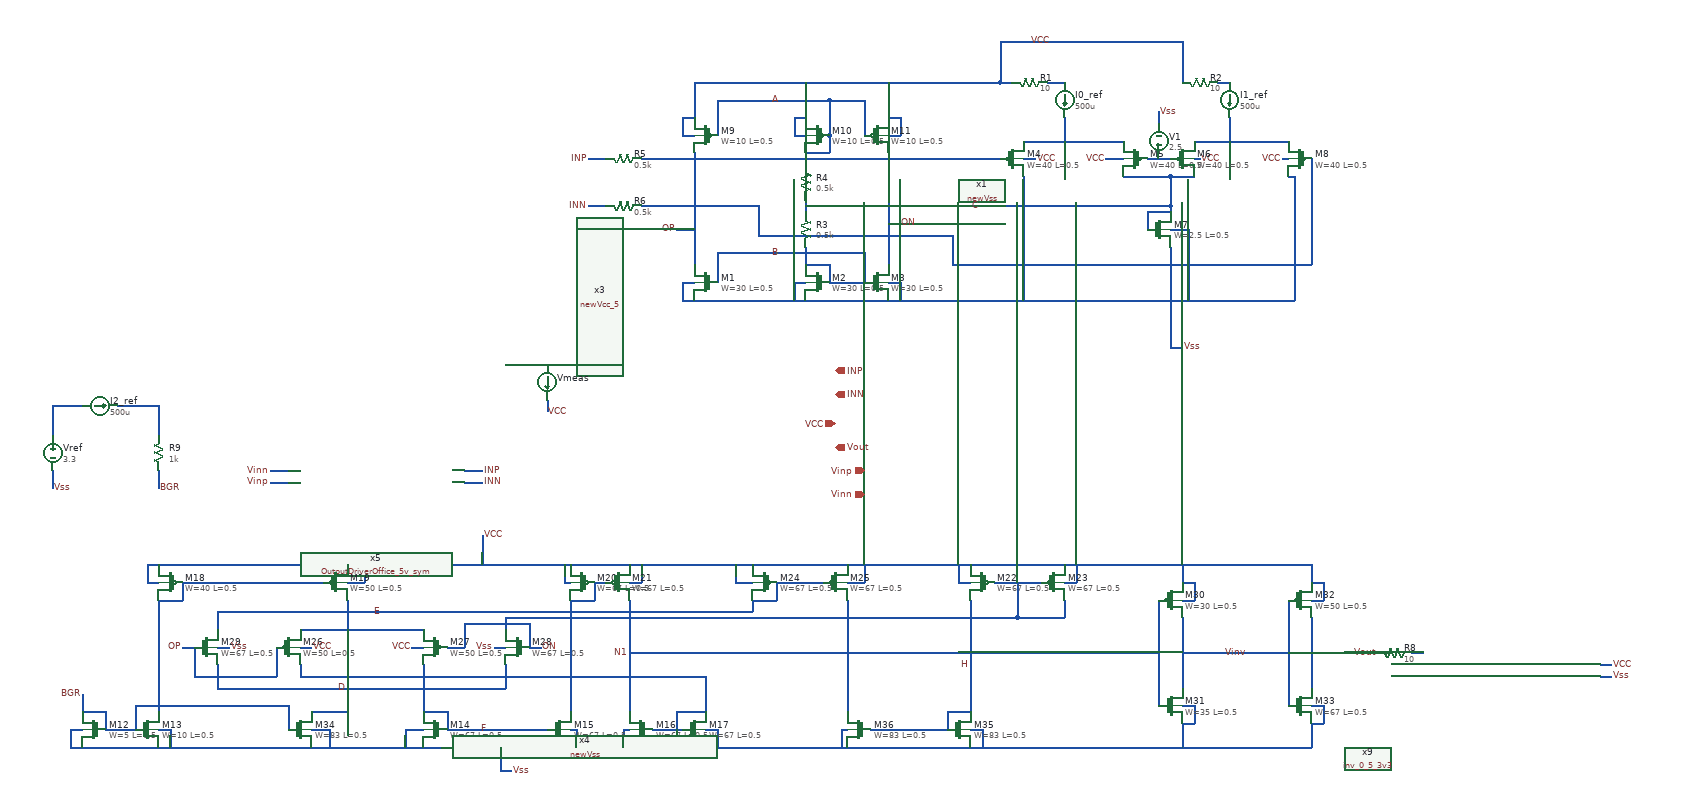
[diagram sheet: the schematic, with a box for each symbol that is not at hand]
v {xschem version=3.4.2 file_version=1.2
}
G {}
K {}
V {}
S {}
E {}
N -170 120 -140 120 {
lab=INP}
N -170 140 -140 140 {
lab=INN}
N -500 120 -470 120 {
lab=Vinn}
N -500 140 -470 140 {
lab=Vinp}
N 550 -420 550 -230 {
lab=ON}
N 780 -440 950 -440 {
lab=#net1}
N 1070 -440 1230 -440 {
lab=#net2}
N 220 -540 220 -480 {
lab=VCC}
N 1130 -480 1130 -440 {
lab=#net2}
N 850 -480 850 -440 {
lab=#net1}
N 990 -410 1030 -410 {
lab=#net3}
N 220 -170 1240 -170 {
lab=Vss}
N 1240 -380 1240 -170 {
lab=Vss}
N 1230 -380 1240 -380 {
lab=Vss}
N 410 -540 410 -480 {
lab=VCC}
N 550 -540 550 -480 {
lab=VCC}
N 220 -340 220 -320 {
lab=OP}
N 220 -420 220 -400 {
lab=OP}
N 220 -260 220 -230 {
lab=OP}
N 410 -420 410 -400 {
lab=A}
N 410 -340 410 -320 {
lab=C}
N 410 -260 410 -230 {
lab=B}
N 410 -330 1030 -330 {
lab=C}
N 1030 -380 1030 -330 {
lab=C}
N 1030 -380 1070 -380 {
lab=C}
N 950 -380 1030 -380 {
lab=C}
N 780 -380 780 -170 {
lab=Vss}
N 1030 -330 1030 -320 {
lab=C}
N 1270 -410 1270 -230 {
lab=ON}
N 660 -230 1270 -230 {
lab=ON}
N 660 -240 660 -230 {
lab=ON}
N 260 -510 260 -450 {
lab=A}
N 260 -510 450 -510 {
lab=A}
N 450 -510 450 -450 {
lab=A}
N 450 -510 510 -510 {
lab=A}
N 510 -510 510 -450 {
lab=A}
N 450 -510 450 -450 {
lab=A}
N 40 -410 70 -410 {
lab=INP}
N 40 -330 70 -330 {
lab=INN}
N 260 -250 260 -200 {
lab=B}
N 260 -250 450 -250 {
lab=B}
N 450 -250 510 -250 {
lab=B}
N 510 -250 510 -200 {
lab=B}
N 200 -200 220 -200 {
lab=Vss}
N 200 -200 200 -170 {
lab=Vss}
N 200 -170 220 -170 {
lab=Vss}
N 390 -200 410 -200 {
lab=Vss}
N 390 -200 390 -170 {
lab=Vss}
N 550 -200 570 -200 {
lab=Vss}
N 570 -200 570 -170 {
lab=Vss}
N 1030 -290 1060 -290 {
lab=Vss}
N 1060 -290 1060 -170 {
lab=Vss}
N 1220 -410 1230 -410 {
lab=VCC}
N 740 -610 740 -540 {
lab=VCC}
N 740 -610 790 -610 {
lab=VCC}
N 920 -410 950 -410 {
lab=VCC}
N 780 -410 800 -410 {
lab=VCC}
N 550 -450 570 -450 {
lab=VCC}
N 570 -480 570 -450 {
lab=VCC}
N 550 -480 570 -480 {
lab=VCC}
N 390 -450 410 -450 {
lab=VCC}
N 390 -480 390 -450 {
lab=VCC}
N 390 -480 410 -480 {
lab=VCC}
N 200 -450 220 -450 {
lab=VCC}
N 200 -480 200 -450 {
lab=VCC}
N 200 -480 220 -480 {
lab=VCC}
N 1070 -410 1080 -410 {
lab=VCC}
N 1030 -260 1030 -170 {
lab=Vss}
N 1030 -170 1030 -90 {
lab=Vss}
N 220 -400 220 -340 {
lab=OP}
N 220 -320 220 -260 {
lab=OP}
N 190 -290 220 -290 {
lab=OP}
N 550 -300 570 -300 {
lab=ON}
N 410 -420 450 -420 {
lab=A}
N 450 -450 450 -420 {
lab=A}
N 820 -540 850 -540 {
lab=#net4}
N 790 -610 1050 -610 {
lab=VCC}
N 1050 -610 1050 -540 {
lab=VCC}
N 1110 -540 1130 -540 {
lab=#net5}
N 740 -540 760 -540 {
lab=VCC}
N 220 -540 740 -540 {
lab=VCC}
N 130 -410 220 -410 {
lab=OP}
N 220 -410 740 -410 {
lab=OP}
N 550 -280 660 -280 {
lab=ON}
N 660 -280 660 -240 {
lab=ON}
N 130 -330 320 -330 {
lab=ON}
N 320 -330 330 -330 {
lab=ON}
N 450 -230 450 -200 {
lab=B}
N 410 -230 450 -230 {
lab=B}
N 990 -320 990 -290 {
lab=C}
N 990 -320 1030 -320 {
lab=C}
N 330 -330 330 -280 {
lab=ON}
N 330 -280 550 -280 {
lab=ON}
N 450 -200 510 -200 {
lab=B}
N 1010 -490 1010 -470 {
lab=Vss}
N 1030 -90 1050 -90 {
lab=Vss}
N -650 310 -410 310 {
lab=#net6}
N 730 310 810 310 {
lab=#net7}
N 360 310 440 310 {
lab=E}
N -690 280 1270 280 {
lab=VCC}
N 1270 280 1270 310 {
lab=VCC}
N 1050 280 1050 310 {
lab=VCC}
N 1050 370 1050 490 {
lab=Vinv}
N 1270 370 1270 490 {
lab=Vout}
N -690 340 -690 530 {
lab=#net6}
N -450 390 -240 390 {
lab=#net8}
N -370 340 -370 390 {
lab=#net8}
N -590 450 -590 490 {
lab=D}
N -590 490 -230 490 {
lab=D}
N -370 490 -370 530 {
lab=D}
N -430 530 -370 530 {
lab=D}
N -240 450 -240 530 {
lab=F}
N -780 560 -730 560 {
lab=BGR}
N -730 520 -730 560 {
lab=BGR}
N -730 520 -470 520 {
lab=BGR}
N -470 520 -470 560 {
lab=BGR}
N -240 530 -200 530 {
lab=F}
N -200 530 -200 560 {
lab=F}
N -200 560 -110 560 {
lab=F}
N 10 340 10 530 {
lab=#net9}
N 170 560 200 560 {
lab=#net10}
N 190 530 190 560 {
lab=#net10}
N 190 530 240 530 {
lab=#net10}
N -450 450 -450 470 {
lab=#net10}
N 110 340 110 530 {
lab=N1}
N -450 470 240 470 {
lab=#net10}
N 240 470 240 530 {
lab=#net10}
N 1270 550 1270 570 {
lab=Vss}
N 1270 570 1270 590 {
lab=Vss}
N -820 590 1270 590 {
lab=Vss}
N 1050 550 1050 590 {
lab=Vss}
N 1230 340 1230 520 {
lab=Vinv}
N 1050 430 1230 430 {
lab=Vinv}
N 1270 430 1340 430 {
lab=Vout}
N -820 500 -820 530 {
lab=BGR}
N -650 420 -630 420 {
lab=OP}
N 690 340 690 500 {
lab=H}
N 490 590 710 590 {
lab=Vss}
N 1010 340 1010 520 {
lab=N1}
N 690 500 690 520 {
lab=H}
N 690 520 690 530 {
lab=H}
N 150 560 170 560 {
lab=#net10}
N 110 430 320 430 {
lab=N1}
N 770 310 770 350 {
lab=#net7}
N -240 590 -210 590 {
lab=Vss}
N -370 280 -340 280 {
lab=VCC}
N -430 590 -400 590 {
lab=Vss}
N -200 420 -170 420 {
lab=ON}
N -60 420 -40 420 {
lab=ON}
N 480 340 480 530 {
lab=N1}
N 520 560 650 560 {
lab=H}
N -110 560 -30 560 {
lab=F}
N -230 490 -100 490 {
lab=D}
N -100 450 -100 490 {
lab=D}
N -60 380 -60 420 {
lab=ON}
N -170 380 -60 380 {
lab=ON}
N -170 380 -170 420 {
lab=ON}
N -590 370 -590 390 {
lab=E}
N -490 420 -490 470 {
lab=OP}
N -620 470 -490 470 {
lab=OP}
N -630 470 -620 470 {
lab=OP}
N -630 420 -630 470 {
lab=OP}
N 50 310 70 310 {
lab=#net9}
N -590 360 -590 370 {
lab=E}
N 1270 340 1290 340 {
lab=VCC}
N 1290 310 1290 340 {
lab=VCC}
N 1270 310 1290 310 {
lab=VCC}
N 1270 520 1290 520 {
lab=Vss}
N 1290 520 1290 550 {
lab=Vss}
N 1270 550 1290 550 {
lab=Vss}
N 1050 520 1070 520 {
lab=Vss}
N 1070 520 1070 550 {
lab=Vss}
N 1050 550 1070 550 {
lab=Vss}
N 1050 340 1070 340 {
lab=VCC}
N 1070 310 1070 340 {
lab=VCC}
N 1050 310 1070 310 {
lab=VCC}
N 850 310 870 310 {
lab=VCC}
N 870 280 870 310 {
lab=VCC}
N 670 310 690 310 {
lab=VCC}
N 670 280 670 310 {
lab=VCC}
N 480 310 510 310 {
lab=VCC}
N 510 280 510 310 {
lab=VCC}
N 290 310 320 310 {
lab=VCC}
N 290 280 290 310 {
lab=VCC}
N 110 310 130 310 {
lab=VCC}
N 130 280 130 310 {
lab=VCC}
N 0 310 10 310 {
lab=VCC}
N 0 280 0 310 {
lab=VCC}
N -370 310 -340 310 {
lab=VCC}
N -340 280 -340 310 {
lab=VCC}
N -710 310 -690 310 {
lab=VCC}
N -710 280 -710 310 {
lab=VCC}
N -710 280 -690 280 {
lab=VCC}
N -840 560 -820 560 {
lab=Vss}
N -840 560 -840 590 {
lab=Vss}
N -840 590 -820 590 {
lab=Vss}
N -690 560 -670 560 {
lab=Vss}
N -670 560 -670 590 {
lab=Vss}
N -430 560 -400 560 {
lab=Vss}
N -400 560 -400 590 {
lab=Vss}
N -270 560 -240 560 {
lab=Vss}
N -270 560 -270 590 {
lab=Vss}
N 10 560 20 560 {
lab=Vss}
N 20 560 20 590 {
lab=Vss}
N 240 560 260 560 {
lab=Vss}
N 260 560 260 590 {
lab=Vss}
N 470 560 480 560 {
lab=Vss}
N 470 560 470 590 {
lab=Vss}
N 690 560 710 560 {
lab=Vss}
N 710 560 710 590 {
lab=Vss}
N -590 420 -570 420 {
lab=Vss}
N -450 420 -430 420 {
lab=VCC}
N -260 420 -240 420 {
lab=VCC}
N -120 420 -100 420 {
lab=Vss}
N -110 590 -110 630 {
lab=Vss}
N -140 230 -140 280 {
lab=VCC}
N 100 560 110 560 {
lab=Vss}
N 100 560 100 590 {
lab=Vss}
N -110 630 -90 630 {
lab=Vss}
N 50 310 50 340 {
lab=#net9}
N 10 340 50 340 {
lab=#net9}
N 650 530 650 560 {
lab=H}
N 650 530 690 530 {
lab=H}
N -780 530 -780 560 {
lab=BGR}
N -820 530 -780 530 {
lab=BGR}
N -650 310 -650 340 {
lab=#net6}
N -690 340 -650 340 {
lab=#net6}
N -100 370 -100 390 {
lab=#net7}
N -100 370 770 370 {
lab=#net7}
N 770 350 770 370 {
lab=#net7}
N 360 310 360 340 {
lab=E}
N 320 340 360 340 {
lab=E}
N -590 360 320 360 {
lab=E}
N 320 340 320 360 {
lab=E}
N 850 340 850 370 {
lab=#net7}
N 770 370 850 370 {
lab=#net7}
N -690 120 -690 150 {
lab=BGR}
N -870 120 -870 150 {
lab=Vss}
N -870 10 -870 60 {
lab=#net11}
N -870 10 -820 10 {
lab=#net11}
N -760 10 -690 10 {
lab=#net12}
N -690 10 -690 60 {
lab=#net12}
N 320 430 480 430 {
lab=N1}
N 480 430 1010 430 {
lab=N1}
N 1340 430 1380 430 {
lab=Vout}
N 1440 430 1460 430 {
lab=#net13}
N 1760 450 1780 450 {
lab=VCC}
N 1760 470 1780 470 {
lab=Vss}
N -100 -60 -30 -60 {
lab=#net14}
N -30 0 -30 20 {
lab=VCC}
C {OutputDriverOffice_5v_sym.sym} -320 130 0 0 {name=x5}
C {devices/lab_pin.sym} -140 120 0 1 {name=p21 sig_type=std_logic lab=INP}
C {devices/lab_pin.sym} -140 140 0 1 {name=p22 sig_type=std_logic lab=INN}
C {devices/lab_pin.sym} -500 120 2 1 {name=p23 sig_type=std_logic lab=Vinn}
C {devices/lab_pin.sym} -500 140 2 1 {name=p24 sig_type=std_logic lab=Vinp}
C {sky130_fd_pr/nfet_g5v0d10v5.sym} 240 -200 0 1 {name=M1
L=0.5
W=30
nf=2
mult=1
ad="'int((nf+1)/2) * W/nf * 0.29'" 
pd="'2*int((nf+1)/2) * (W/nf + 0.29)'"
as="'int((nf+2)/2) * W/nf * 0.29'" 
ps="'2*int((nf+2)/2) * (W/nf + 0.29)'"
nrd="'0.29 / W'" nrs="'0.29 / W'"
sa=0 sb=0 sd=0
model=nfet_g5v0d10v5
spiceprefix=X
}
C {sky130_fd_pr/nfet_g5v0d10v5.sym} 430 -200 0 1 {name=M2
L=0.5
W=30
nf=2
mult=1
ad="'int((nf+1)/2) * W/nf * 0.29'" 
pd="'2*int((nf+1)/2) * (W/nf + 0.29)'"
as="'int((nf+2)/2) * W/nf * 0.29'" 
ps="'2*int((nf+2)/2) * (W/nf + 0.29)'"
nrd="'0.29 / W'" nrs="'0.29 / W'"
sa=0 sb=0 sd=0
model=nfet_g5v0d10v5
spiceprefix=X
}
C {sky130_fd_pr/nfet_g5v0d10v5.sym} 530 -200 0 0 {name=M3
L=0.5
W=30
nf=2
mult=1
ad="'int((nf+1)/2) * W/nf * 0.29'" 
pd="'2*int((nf+1)/2) * (W/nf + 0.29)'"
as="'int((nf+2)/2) * W/nf * 0.29'" 
ps="'2*int((nf+2)/2) * (W/nf + 0.29)'"
nrd="'0.29 / W'" nrs="'0.29 / W'"
sa=0 sb=0 sd=0
model=nfet_g5v0d10v5
spiceprefix=X
}
C {sky130_fd_pr/pfet_g5v0d10v5.sym} 240 -450 0 1 {name=M9
L=0.5
W=10
nf=1
mult=1
ad="'int((nf+1)/2) * W/nf * 0.29'" 
pd="'2*int((nf+1)/2) * (W/nf + 0.29)'"
as="'int((nf+2)/2) * W/nf * 0.29'" 
ps="'2*int((nf+2)/2) * (W/nf + 0.29)'"
nrd="'0.29 / W'" nrs="'0.29 / W'"
sa=0 sb=0 sd=0
model=pfet_g5v0d10v5
spiceprefix=X
}
C {sky130_fd_pr/pfet_g5v0d10v5.sym} 430 -450 0 1 {name=M10
L=0.5
W=10
nf=1
mult=1
ad="'int((nf+1)/2) * W/nf * 0.29'" 
pd="'2*int((nf+1)/2) * (W/nf + 0.29)'"
as="'int((nf+2)/2) * W/nf * 0.29'" 
ps="'2*int((nf+2)/2) * (W/nf + 0.29)'"
nrd="'0.29 / W'" nrs="'0.29 / W'"
sa=0 sb=0 sd=0
model=pfet_g5v0d10v5
spiceprefix=X
}
C {sky130_fd_pr/pfet_g5v0d10v5.sym} 530 -450 0 0 {name=M11
L=0.5
W=10
nf=1
mult=1
ad="'int((nf+1)/2) * W/nf * 0.29'" 
pd="'2*int((nf+1)/2) * (W/nf + 0.29)'"
as="'int((nf+2)/2) * W/nf * 0.29'" 
ps="'2*int((nf+2)/2) * (W/nf + 0.29)'"
nrd="'0.29 / W'" nrs="'0.29 / W'"
sa=0 sb=0 sd=0
model=pfet_g5v0d10v5
spiceprefix=X
}
C {/home/saumeek/simulation_library/newVss.sym} 880 -90 0 0 {name=x1}
C {devices/isource.sym} 850 -510 0 0 {name=I0_ref value=500u}
C {devices/isource.sym} 1130 -510 0 0 {name=I1_ref value=500u}
C {devices/res.sym} 410 -290 0 0 {name=R3
value=0.5k
footprint=1206
device=resistor
m=1}
C {devices/res.sym} 410 -370 0 0 {name=R4
value=0.5k
footprint=1206
device=resistor
m=1}
C {devices/res.sym} 100 -410 1 0 {name=R5
value=0.5k
footprint=1206
device=resistor
m=1}
C {devices/res.sym} 100 -330 1 0 {name=R6
value=0.5k
footprint=1206
device=resistor
m=1}
C {devices/lab_pin.sym} 790 -610 0 1 {name=p1 sig_type=std_logic lab=VCC}
C {devices/lab_pin.sym} 800 -410 0 1 {name=p2 sig_type=std_logic lab=VCC}
C {devices/lab_pin.sym} 920 -410 0 0 {name=p3 sig_type=std_logic lab=VCC}
C {devices/lab_pin.sym} 1080 -410 0 1 {name=p4 sig_type=std_logic lab=VCC}
C {devices/lab_pin.sym} 1220 -410 0 0 {name=p5 sig_type=std_logic lab=VCC}
C {devices/lab_pin.sym} 40 -410 0 0 {name=p6 sig_type=std_logic lab=INP}
C {devices/lab_pin.sym} 40 -330 0 0 {name=p7 sig_type=std_logic lab=INN}
C {devices/lab_pin.sym} 190 -290 0 0 {name=p8 sig_type=std_logic lab=OP}
C {devices/lab_pin.sym} 570 -300 0 1 {name=p9 sig_type=std_logic lab=ON}
C {sky130_fd_pr/nfet_g5v0d10v5.sym} 1010 -290 0 0 {name=M7
L=0.5
W=2.5
nf=1
mult=1
ad="'int((nf+1)/2) * W/nf * 0.29'" 
pd="'2*int((nf+1)/2) * (W/nf + 0.29)'"
as="'int((nf+2)/2) * W/nf * 0.29'" 
ps="'2*int((nf+2)/2) * (W/nf + 0.29)'"
nrd="'0.29 / W'" nrs="'0.29 / W'"
sa=0 sb=0 sd=0
model=nfet_g5v0d10v5
spiceprefix=X
}
C {sky130_fd_pr/pfet_g5v0d10v5.sym} 760 -410 0 0 {name=M4
L=0.5
W=40
nf=1
mult=1
ad="'int((nf+1)/2) * W/nf * 0.29'" 
pd="'2*int((nf+1)/2) * (W/nf + 0.29)'"
as="'int((nf+2)/2) * W/nf * 0.29'" 
ps="'2*int((nf+2)/2) * (W/nf + 0.29)'"
nrd="'0.29 / W'" nrs="'0.29 / W'"
sa=0 sb=0 sd=0
model=pfet_g5v0d10v5
spiceprefix=X
}
C {sky130_fd_pr/pfet_g5v0d10v5.sym} 970 -410 0 1 {name=M5
L=0.5
W=40
nf=1
mult=1
ad="'int((nf+1)/2) * W/nf * 0.29'" 
pd="'2*int((nf+1)/2) * (W/nf + 0.29)'"
as="'int((nf+2)/2) * W/nf * 0.29'" 
ps="'2*int((nf+2)/2) * (W/nf + 0.29)'"
nrd="'0.29 / W'" nrs="'0.29 / W'"
sa=0 sb=0 sd=0
model=pfet_g5v0d10v5
spiceprefix=X
}
C {sky130_fd_pr/pfet_g5v0d10v5.sym} 1050 -410 0 0 {name=M6
L=0.5
W=40
nf=1
mult=1
ad="'int((nf+1)/2) * W/nf * 0.29'" 
pd="'2*int((nf+1)/2) * (W/nf + 0.29)'"
as="'int((nf+2)/2) * W/nf * 0.29'" 
ps="'2*int((nf+2)/2) * (W/nf + 0.29)'"
nrd="'0.29 / W'" nrs="'0.29 / W'"
sa=0 sb=0 sd=0
model=pfet_g5v0d10v5
spiceprefix=X
}
C {sky130_fd_pr/pfet_g5v0d10v5.sym} 1250 -410 0 1 {name=M8
L=0.5
W=40
nf=1
mult=1
ad="'int((nf+1)/2) * W/nf * 0.29'" 
pd="'2*int((nf+1)/2) * (W/nf + 0.29)'"
as="'int((nf+2)/2) * W/nf * 0.29'" 
ps="'2*int((nf+2)/2) * (W/nf + 0.29)'"
nrd="'0.29 / W'" nrs="'0.29 / W'"
sa=0 sb=0 sd=0
model=pfet_g5v0d10v5
spiceprefix=X
}
C {devices/vsource.sym} 1010 -440 2 0 {name=V1 value=2.5}
C {devices/res.sym} 790 -540 1 0 {name=R1
value=10
footprint=1206
device=resistor
m=1}
C {devices/res.sym} 1080 -540 1 0 {name=R2
value=10
footprint=1206
device=resistor
m=1}
C {devices/lab_pin.sym} 350 -510 0 1 {name=p29 sig_type=std_logic lab=A}
C {devices/lab_pin.sym} 350 -250 0 1 {name=p30 sig_type=std_logic lab=B}
C {devices/lab_pin.sym} 690 -330 0 1 {name=p31 sig_type=std_logic lab=C}
C {devices/lab_pin.sym} 1010 -490 0 1 {name=p32 sig_type=std_logic lab=Vss}
C {devices/lab_pin.sym} 1050 -90 0 1 {name=p33 sig_type=std_logic lab=Vss}
C {sky130_fd_pr/nfet_g5v0d10v5.sym} -800 560 0 1 {name=M12
L=0.5
W=5
nf=1
mult=1
ad="'int((nf+1)/2) * W/nf * 0.29'" 
pd="'2*int((nf+1)/2) * (W/nf + 0.29)'"
as="'int((nf+2)/2) * W/nf * 0.29'" 
ps="'2*int((nf+2)/2) * (W/nf + 0.29)'"
nrd="'0.29 / W'" nrs="'0.29 / W'"
sa=0 sb=0 sd=0
model=nfet_g5v0d10v5
spiceprefix=X
}
C {sky130_fd_pr/nfet_g5v0d10v5.sym} -710 560 0 0 {name=M13
L=0.5
W=10
nf=1
mult=1
ad="'int((nf+1)/2) * W/nf * 0.29'" 
pd="'2*int((nf+1)/2) * (W/nf + 0.29)'"
as="'int((nf+2)/2) * W/nf * 0.29'" 
ps="'2*int((nf+2)/2) * (W/nf + 0.29)'"
nrd="'0.29 / W'" nrs="'0.29 / W'"
sa=0 sb=0 sd=0
model=nfet_g5v0d10v5
spiceprefix=X
}
C {sky130_fd_pr/nfet_g5v0d10v5.sym} -220 560 0 1 {name=M14
L=0.5
W=67
nf=1
mult=1
ad="'int((nf+1)/2) * W/nf * 0.29'" 
pd="'2*int((nf+1)/2) * (W/nf + 0.29)'"
as="'int((nf+2)/2) * W/nf * 0.29'" 
ps="'2*int((nf+2)/2) * (W/nf + 0.29)'"
nrd="'0.29 / W'" nrs="'0.29 / W'"
sa=0 sb=0 sd=0
model=nfet_g5v0d10v5
spiceprefix=X
}
C {sky130_fd_pr/nfet_g5v0d10v5.sym} -10 560 0 0 {name=M15
L=0.5
W=67
nf=1
mult=1
ad="'int((nf+1)/2) * W/nf * 0.29'" 
pd="'2*int((nf+1)/2) * (W/nf + 0.29)'"
as="'int((nf+2)/2) * W/nf * 0.29'" 
ps="'2*int((nf+2)/2) * (W/nf + 0.29)'"
nrd="'0.29 / W'" nrs="'0.29 / W'"
sa=0 sb=0 sd=0
model=nfet_g5v0d10v5
spiceprefix=X
}
C {sky130_fd_pr/nfet_g5v0d10v5.sym} 130 560 0 1 {name=M16
L=0.5
W=67
nf=1
mult=1
ad="'int((nf+1)/2) * W/nf * 0.29'" 
pd="'2*int((nf+1)/2) * (W/nf + 0.29)'"
as="'int((nf+2)/2) * W/nf * 0.29'" 
ps="'2*int((nf+2)/2) * (W/nf + 0.29)'"
nrd="'0.29 / W'" nrs="'0.29 / W'"
sa=0 sb=0 sd=0
model=nfet_g5v0d10v5
spiceprefix=X
}
C {sky130_fd_pr/nfet_g5v0d10v5.sym} 220 560 0 0 {name=M17
L=0.5
W=67
nf=1
mult=1
ad="'int((nf+1)/2) * W/nf * 0.29'" 
pd="'2*int((nf+1)/2) * (W/nf + 0.29)'"
as="'int((nf+2)/2) * W/nf * 0.29'" 
ps="'2*int((nf+2)/2) * (W/nf + 0.29)'"
nrd="'0.29 / W'" nrs="'0.29 / W'"
sa=0 sb=0 sd=0
model=nfet_g5v0d10v5
spiceprefix=X
}
C {sky130_fd_pr/pfet_g5v0d10v5.sym} -670 310 0 1 {name=M18
L=0.5
W=40
nf=1
mult=1
ad="'int((nf+1)/2) * W/nf * 0.29'" 
pd="'2*int((nf+1)/2) * (W/nf + 0.29)'"
as="'int((nf+2)/2) * W/nf * 0.29'" 
ps="'2*int((nf+2)/2) * (W/nf + 0.29)'"
nrd="'0.29 / W'" nrs="'0.29 / W'"
sa=0 sb=0 sd=0
model=pfet_g5v0d10v5
spiceprefix=X
}
C {sky130_fd_pr/pfet_g5v0d10v5.sym} -390 310 0 0 {name=M19
L=0.5
W=50
nf=2
mult=1
ad="'int((nf+1)/2) * W/nf * 0.29'" 
pd="'2*int((nf+1)/2) * (W/nf + 0.29)'"
as="'int((nf+2)/2) * W/nf * 0.29'" 
ps="'2*int((nf+2)/2) * (W/nf + 0.29)'"
nrd="'0.29 / W'" nrs="'0.29 / W'"
sa=0 sb=0 sd=0
model=pfet_g5v0d10v5
spiceprefix=X
}
C {sky130_fd_pr/pfet_g5v0d10v5.sym} 30 310 0 1 {name=M20
L=0.5
W=67
nf=1
mult=1
ad="'int((nf+1)/2) * W/nf * 0.29'" 
pd="'2*int((nf+1)/2) * (W/nf + 0.29)'"
as="'int((nf+2)/2) * W/nf * 0.29'" 
ps="'2*int((nf+2)/2) * (W/nf + 0.29)'"
nrd="'0.29 / W'" nrs="'0.29 / W'"
sa=0 sb=0 sd=0
model=pfet_g5v0d10v5
spiceprefix=X
}
C {sky130_fd_pr/pfet_g5v0d10v5.sym} 90 310 0 0 {name=M21
L=0.5
W=67
nf=1
mult=1
ad="'int((nf+1)/2) * W/nf * 0.29'" 
pd="'2*int((nf+1)/2) * (W/nf + 0.29)'"
as="'int((nf+2)/2) * W/nf * 0.29'" 
ps="'2*int((nf+2)/2) * (W/nf + 0.29)'"
nrd="'0.29 / W'" nrs="'0.29 / W'"
sa=0 sb=0 sd=0
model=pfet_g5v0d10v5
spiceprefix=X
}
C {sky130_fd_pr/pfet_g5v0d10v5.sym} 710 310 0 1 {name=M22
L=0.5
W=67
nf=2
mult=1
ad="'int((nf+1)/2) * W/nf * 0.29'" 
pd="'2*int((nf+1)/2) * (W/nf + 0.29)'"
as="'int((nf+2)/2) * W/nf * 0.29'" 
ps="'2*int((nf+2)/2) * (W/nf + 0.29)'"
nrd="'0.29 / W'" nrs="'0.29 / W'"
sa=0 sb=0 sd=0
model=pfet_g5v0d10v5
spiceprefix=X
}
C {sky130_fd_pr/pfet_g5v0d10v5.sym} 830 310 0 0 {name=M23
L=0.5
W=67
nf=2
mult=1
ad="'int((nf+1)/2) * W/nf * 0.29'" 
pd="'2*int((nf+1)/2) * (W/nf + 0.29)'"
as="'int((nf+2)/2) * W/nf * 0.29'" 
ps="'2*int((nf+2)/2) * (W/nf + 0.29)'"
nrd="'0.29 / W'" nrs="'0.29 / W'"
sa=0 sb=0 sd=0
model=pfet_g5v0d10v5
spiceprefix=X
}
C {sky130_fd_pr/pfet_g5v0d10v5.sym} 340 310 0 1 {name=M24
L=0.5
W=67
nf=1
mult=1
ad="'int((nf+1)/2) * W/nf * 0.29'" 
pd="'2*int((nf+1)/2) * (W/nf + 0.29)'"
as="'int((nf+2)/2) * W/nf * 0.29'" 
ps="'2*int((nf+2)/2) * (W/nf + 0.29)'"
nrd="'0.29 / W'" nrs="'0.29 / W'"
sa=0 sb=0 sd=0
model=pfet_g5v0d10v5
spiceprefix=X
}
C {sky130_fd_pr/pfet_g5v0d10v5.sym} 460 310 0 0 {name=M25
L=0.5
W=67
nf=2
mult=1
ad="'int((nf+1)/2) * W/nf * 0.29'" 
pd="'2*int((nf+1)/2) * (W/nf + 0.29)'"
as="'int((nf+2)/2) * W/nf * 0.29'" 
ps="'2*int((nf+2)/2) * (W/nf + 0.29)'"
nrd="'0.29 / W'" nrs="'0.29 / W'"
sa=0 sb=0 sd=0
model=pfet_g5v0d10v5
spiceprefix=X
}
C {sky130_fd_pr/pfet_g5v0d10v5.sym} -470 420 0 0 {name=M26
L=0.5
W=50
nf=4
mult=1
ad="'int((nf+1)/2) * W/nf * 0.29'" 
pd="'2*int((nf+1)/2) * (W/nf + 0.29)'"
as="'int((nf+2)/2) * W/nf * 0.29'" 
ps="'2*int((nf+2)/2) * (W/nf + 0.29)'"
nrd="'0.29 / W'" nrs="'0.29 / W'"
sa=0 sb=0 sd=0
model=pfet_g5v0d10v5
spiceprefix=X
}
C {sky130_fd_pr/pfet_g5v0d10v5.sym} -220 420 0 1 {name=M27
L=0.5
W=50
nf=4
mult=1
ad="'int((nf+1)/2) * W/nf * 0.29'" 
pd="'2*int((nf+1)/2) * (W/nf + 0.29)'"
as="'int((nf+2)/2) * W/nf * 0.29'" 
ps="'2*int((nf+2)/2) * (W/nf + 0.29)'"
nrd="'0.29 / W'" nrs="'0.29 / W'"
sa=0 sb=0 sd=0
model=pfet_g5v0d10v5
spiceprefix=X
}
C {sky130_fd_pr/nfet_g5v0d10v5.sym} -80 420 0 1 {name=M28
L=0.5
W=67
nf=1
mult=1
ad="'int((nf+1)/2) * W/nf * 0.29'" 
pd="'2*int((nf+1)/2) * (W/nf + 0.29)'"
as="'int((nf+2)/2) * W/nf * 0.29'" 
ps="'2*int((nf+2)/2) * (W/nf + 0.29)'"
nrd="'0.29 / W'" nrs="'0.29 / W'"
sa=0 sb=0 sd=0
model=nfet_g5v0d10v5
spiceprefix=X
}
C {sky130_fd_pr/nfet_g5v0d10v5.sym} -610 420 0 0 {name=M29
L=0.5
W=67
nf=1
mult=1
ad="'int((nf+1)/2) * W/nf * 0.29'" 
pd="'2*int((nf+1)/2) * (W/nf + 0.29)'"
as="'int((nf+2)/2) * W/nf * 0.29'" 
ps="'2*int((nf+2)/2) * (W/nf + 0.29)'"
nrd="'0.29 / W'" nrs="'0.29 / W'"
sa=0 sb=0 sd=0
model=nfet_g5v0d10v5
spiceprefix=X
}
C {sky130_fd_pr/pfet_g5v0d10v5.sym} 1030 340 0 0 {name=M30
L=0.5
W=30
nf=1
mult=1
ad="'int((nf+1)/2) * W/nf * 0.29'" 
pd="'2*int((nf+1)/2) * (W/nf + 0.29)'"
as="'int((nf+2)/2) * W/nf * 0.29'" 
ps="'2*int((nf+2)/2) * (W/nf + 0.29)'"
nrd="'0.29 / W'" nrs="'0.29 / W'"
sa=0 sb=0 sd=0
model=pfet_g5v0d10v5
spiceprefix=X
}
C {sky130_fd_pr/nfet_g5v0d10v5.sym} 1030 520 0 0 {name=M31
L=0.5
W=35
nf=2
mult=1
ad="'int((nf+1)/2) * W/nf * 0.29'" 
pd="'2*int((nf+1)/2) * (W/nf + 0.29)'"
as="'int((nf+2)/2) * W/nf * 0.29'" 
ps="'2*int((nf+2)/2) * (W/nf + 0.29)'"
nrd="'0.29 / W'" nrs="'0.29 / W'"
sa=0 sb=0 sd=0
model=nfet_g5v0d10v5
spiceprefix=X
}
C {sky130_fd_pr/pfet_g5v0d10v5.sym} 1250 340 0 0 {name=M32
L=0.5
W=50
nf=2
mult=1
ad="'int((nf+1)/2) * W/nf * 0.29'" 
pd="'2*int((nf+1)/2) * (W/nf + 0.29)'"
as="'int((nf+2)/2) * W/nf * 0.29'" 
ps="'2*int((nf+2)/2) * (W/nf + 0.29)'"
nrd="'0.29 / W'" nrs="'0.29 / W'"
sa=0 sb=0 sd=0
model=pfet_g5v0d10v5
spiceprefix=X
}
C {sky130_fd_pr/nfet_g5v0d10v5.sym} 1250 520 0 0 {name=M33
L=0.5
W=67
nf=1
mult=1
ad="'int((nf+1)/2) * W/nf * 0.29'" 
pd="'2*int((nf+1)/2) * (W/nf + 0.29)'"
as="'int((nf+2)/2) * W/nf * 0.29'" 
ps="'2*int((nf+2)/2) * (W/nf + 0.29)'"
nrd="'0.29 / W'" nrs="'0.29 / W'"
sa=0 sb=0 sd=0
model=nfet_g5v0d10v5
spiceprefix=X
}
C {sky130_fd_pr/nfet_g5v0d10v5.sym} -450 560 0 0 {name=M34
L=0.5
W=83
nf=2
mult=1
ad="'int((nf+1)/2) * W/nf * 0.29'" 
pd="'2*int((nf+1)/2) * (W/nf + 0.29)'"
as="'int((nf+2)/2) * W/nf * 0.29'" 
ps="'2*int((nf+2)/2) * (W/nf + 0.29)'"
nrd="'0.29 / W'" nrs="'0.29 / W'"
sa=0 sb=0 sd=0
model=nfet_g5v0d10v5
spiceprefix=X
}
C {sky130_fd_pr/nfet_g5v0d10v5.sym} 670 560 0 0 {name=M35
L=0.5
W=83
nf=1
mult=1
ad="'int((nf+1)/2) * W/nf * 0.29'" 
pd="'2*int((nf+1)/2) * (W/nf + 0.29)'"
as="'int((nf+2)/2) * W/nf * 0.29'" 
ps="'2*int((nf+2)/2) * (W/nf + 0.29)'"
nrd="'0.29 / W'" nrs="'0.29 / W'"
sa=0 sb=0 sd=0
model=nfet_g5v0d10v5
spiceprefix=X
}
C {devices/lab_pin.sym} -820 500 0 0 {name=p10 sig_type=std_logic lab=BGR}
C {devices/lab_pin.sym} -650 420 0 0 {name=p11 sig_type=std_logic lab=OP}
C {devices/lab_pin.sym} -40 420 0 1 {name=p12 sig_type=std_logic lab=ON}
C {devices/lab_pin.sym} 110 430 0 0 {name=p13 sig_type=std_logic lab=N1}
C {sky130_fd_pr/nfet_g5v0d10v5.sym} 500 560 0 1 {name=M36
L=0.5
W=83
nf=1
mult=1
ad="'int((nf+1)/2) * W/nf * 0.29'" 
pd="'2*int((nf+1)/2) * (W/nf + 0.29)'"
as="'int((nf+2)/2) * W/nf * 0.29'" 
ps="'2*int((nf+2)/2) * (W/nf + 0.29)'"
nrd="'0.29 / W'" nrs="'0.29 / W'"
sa=0 sb=0 sd=0
model=nfet_g5v0d10v5
spiceprefix=X
}
C {devices/lab_pin.sym} -120 420 0 0 {name=p14 sig_type=std_logic lab=Vss}
C {devices/lab_pin.sym} -260 420 0 0 {name=p15 sig_type=std_logic lab=VCC}
C {devices/lab_pin.sym} -430 420 0 1 {name=p16 sig_type=std_logic lab=VCC}
C {devices/lab_pin.sym} -570 420 0 1 {name=p17 sig_type=std_logic lab=Vss}
C {/home/saumeek/simulation_library/newVcc_5.sym} -250 -60 0 0 {name=x3}
C {/home/saumeek/simulation_library/newVss.sym} -260 630 0 0 {name=x4}
C {devices/lab_pin.sym} -140 230 0 1 {name=p18 sig_type=std_logic lab=VCC}
C {devices/lab_pin.sym} -90 630 0 1 {name=p19 sig_type=std_logic lab=Vss}
C {devices/lab_pin.sym} 1340 430 0 1 {name=p20 sig_type=std_logic lab=Vout}
C {devices/lab_pin.sym} -370 490 0 0 {name=p25 sig_type=std_logic lab=D}
C {devices/lab_pin.sym} -310 360 0 0 {name=p26 sig_type=std_logic lab=E}
C {devices/lab_pin.sym} -130 560 0 0 {name=p27 sig_type=std_logic lab=F}
C {devices/lab_pin.sym} 690 450 0 0 {name=p34 sig_type=std_logic lab=H}
C {devices/isource.sym} -790 10 3 1 {name=I2_ref value=500u}
C {devices/res.sym} -690 90 2 0 {name=R9
value=1k
footprint=1206
device=resistor
m=1}
C {devices/lab_pin.sym} -690 150 0 1 {name=p50 sig_type=std_logic lab=BGR}
C {devices/vsource.sym} -870 90 0 0 {name=Vref value=3.3}
C {devices/lab_pin.sym} -870 150 0 1 {name=p66 sig_type=std_logic lab=Vss}
C {devices/lab_pin.sym} 1120 430 0 1 {name=p35 sig_type=std_logic lab=Vinv}
C {/home/saumeek/simulation_library/inv_0_5_3v3.sym} 1610 450 0 0 {name=x9}
C {devices/res.sym} 1410 430 1 0 {name=R8
value=10
footprint=1206
device=resistor
m=1}
C {devices/lab_pin.sym} 1780 450 0 1 {name=p28 sig_type=std_logic lab=VCC}
C {devices/lab_pin.sym} 1780 470 0 1 {name=p36 sig_type=std_logic lab=Vss}
C {devices/ipin.sym} 510 120 0 0 {name=p37 lab=Vinp}
C {devices/ipin.sym} 510 160 0 0 {name=p38 lab=Vinn}
C {devices/opin.sym} 460 80 0 0 {name=p39 lab=Vout
}
C {devices/iopin.sym} 460 40 0 0 {name=p40 lab=VCC}
C {devices/opin.sym} 460 -10 0 0 {name=p41 lab=INN
}
C {devices/opin.sym} 460 -50 0 0 {name=p42 lab=INP
}
C {devices/ammeter.sym} -30 -30 0 0 {name=Vmeas}
C {devices/lab_pin.sym} -30 20 0 1 {name=p43 sig_type=std_logic lab=VCC}
